One B-rep face of a CAD part: STEP entity #313.
In plain terms, the planar face has unit normal (1, 0, 0).
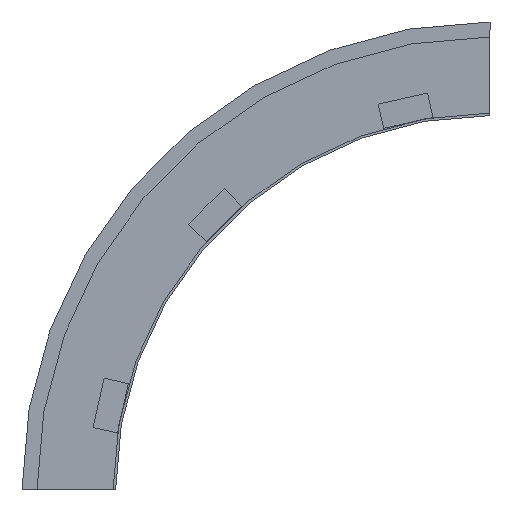
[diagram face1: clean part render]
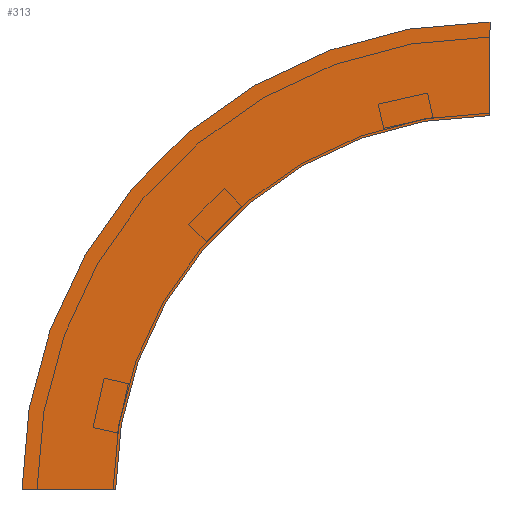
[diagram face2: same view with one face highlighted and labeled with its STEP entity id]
Its self-contained STEP definition (entity closure, numbers rounded to 3 decimals):
#2 = DIRECTION ( 'NONE',  ( 1., 0., 0. ) ) ;
#7 = EDGE_LOOP ( 'NONE', ( #193, #220, #490, #290 ) ) ;
#18 = CIRCLE ( 'NONE', #73, 300. ) ;
#35 = DIRECTION ( 'NONE',  ( 0., 0., 1. ) ) ;
#41 = PLANE ( 'NONE',  #183 ) ;
#73 = AXIS2_PLACEMENT_3D ( 'NONE', #575, #356, #492 ) ;
#91 = EDGE_CURVE ( 'NONE', #105, #93, #440, .T. ) ;
#93 = VERTEX_POINT ( 'NONE', #268 ) ;
#105 = VERTEX_POINT ( 'NONE', #316 ) ;
#133 = VECTOR ( 'NONE', #35, 1000. ) ;
#148 = VERTEX_POINT ( 'NONE', #527 ) ;
#157 = EDGE_CURVE ( 'NONE', #148, #105, #18, .T. ) ;
#163 = CARTESIAN_POINT ( 'NONE',  ( 0., -300., 0. ) ) ;
#171 = VERTEX_POINT ( 'NONE', #306 ) ;
#183 = AXIS2_PLACEMENT_3D ( 'NONE', #419, #2, #227 ) ;
#193 = ORIENTED_EDGE ( 'NONE', *, *, #559, .T. ) ;
#220 = ORIENTED_EDGE ( 'NONE', *, *, #91, .F. ) ;
#223 = AXIS2_PLACEMENT_3D ( 'NONE', #163, #441, #262 ) ;
#227 = DIRECTION ( 'NONE',  ( 0., 0., -1. ) ) ;
#234 = DIRECTION ( 'NONE',  ( 0., 1., 0. ) ) ;
#262 = DIRECTION ( 'NONE',  ( 0., 1., 0. ) ) ;
#267 = EDGE_CURVE ( 'NONE', #148, #171, #326, .T. ) ;
#268 = CARTESIAN_POINT ( 'NONE',  ( 0., -300., 375. ) ) ;
#290 = ORIENTED_EDGE ( 'NONE', *, *, #267, .T. ) ;
#306 = CARTESIAN_POINT ( 'NONE',  ( 0., 75., 0. ) ) ;
#313 = ADVANCED_FACE ( 'NONE', ( #332 ), #41, .T. ) ;
#316 = CARTESIAN_POINT ( 'NONE',  ( 0., -300., 300. ) ) ;
#326 = LINE ( 'NONE', #466, #408 ) ;
#332 = FACE_OUTER_BOUND ( 'NONE', #7, .T. ) ;
#356 = DIRECTION ( 'NONE',  ( 1., 0., 0. ) ) ;
#408 = VECTOR ( 'NONE', #234, 1000. ) ;
#419 = CARTESIAN_POINT ( 'NONE',  ( 0., 0., 0. ) ) ;
#436 = CIRCLE ( 'NONE', #223, 375. ) ;
#440 = LINE ( 'NONE', #539, #133 ) ;
#441 = DIRECTION ( 'NONE',  ( 1., 0., 0. ) ) ;
#466 = CARTESIAN_POINT ( 'NONE',  ( 0., 0., 0. ) ) ;
#490 = ORIENTED_EDGE ( 'NONE', *, *, #157, .F. ) ;
#492 = DIRECTION ( 'NONE',  ( 0., 1., 0. ) ) ;
#527 = CARTESIAN_POINT ( 'NONE',  ( 0., 0., 0. ) ) ;
#539 = CARTESIAN_POINT ( 'NONE',  ( 0., -300., 300. ) ) ;
#559 = EDGE_CURVE ( 'NONE', #171, #93, #436, .T. ) ;
#575 = CARTESIAN_POINT ( 'NONE',  ( 0., -300., 0. ) ) ;
